VERSION 5.7 ;
BUSBITCHARS "[]" ;
DIVIDERCHAR "/" ;

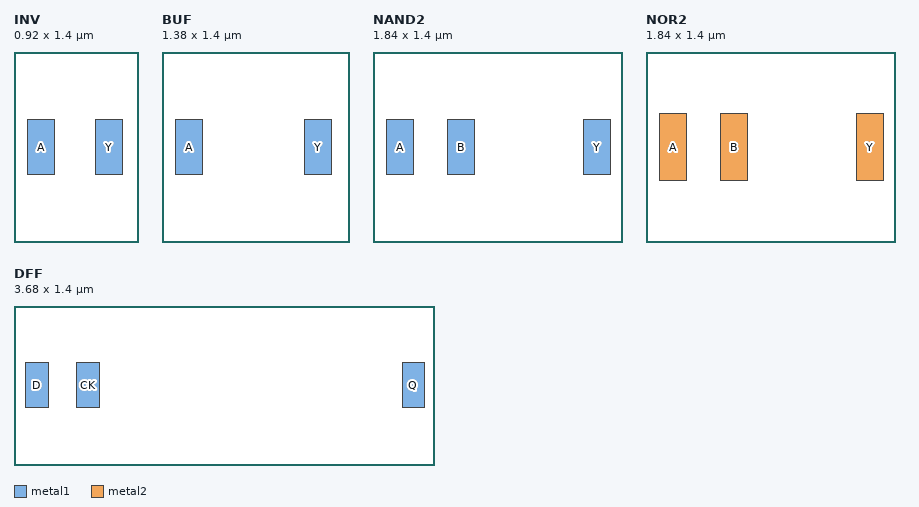
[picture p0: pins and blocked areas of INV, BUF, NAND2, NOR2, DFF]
MACRO INV
  CLASS CORE ;
  ORIGIN 0 0 ;
  SIZE 0.92 BY 1.4 ;
  SYMMETRY X Y ;
  SITE core ;
  PIN A
    DIRECTION INPUT ; USE SIGNAL ;
    PORT LAYER metal1 ; RECT 0.1 0.5 0.3 0.9 ; END
  END A
  PIN Y
    DIRECTION OUTPUT ; USE SIGNAL ;
    PORT LAYER metal1 ; RECT 0.6 0.5 0.8 0.9 ; END
  END Y
END INV

MACRO BUF
  CLASS CORE ;
  ORIGIN 0 0 ;
  SIZE 1.38 BY 1.4 ;
  SYMMETRY X Y ;
  SITE core ;
  PIN A
    DIRECTION INPUT ; USE SIGNAL ;
    PORT LAYER metal1 ; RECT 0.1 0.5 0.3 0.9 ; END
  END A
  PIN Y
    DIRECTION OUTPUT ; USE SIGNAL ;
    PORT LAYER metal1 ; RECT 1.05 0.5 1.25 0.9 ; END
  END Y
END BUF

MACRO NAND2
  CLASS CORE ;
  ORIGIN 0 0 ;
  SIZE 1.84 BY 1.4 ;
  SYMMETRY X Y ;
  SITE core ;
  PIN A
    DIRECTION INPUT ; USE SIGNAL ;
    PORT LAYER metal1 ; RECT 0.1 0.5 0.3 0.9 ; END
  END A
  PIN B
    DIRECTION INPUT ; USE SIGNAL ;
    PORT LAYER metal1 ; RECT 0.55 0.5 0.75 0.9 ; END
  END B
  PIN Y
    DIRECTION OUTPUT ; USE SIGNAL ;
    PORT LAYER metal1 ; RECT 1.55 0.5 1.75 0.9 ; END
  END Y
END NAND2

MACRO NOR2
  CLASS CORE ;
  ORIGIN 0 0 ;
  SIZE 1.84 BY 1.4 ;
  SYMMETRY X Y ;
  SITE core ;
  PIN A
    DIRECTION INPUT ; USE SIGNAL ;
    PORT LAYER metal2 ; RECT 0.1 0.45 0.3 0.95 ; END
  END A
  PIN B
    DIRECTION INPUT ; USE SIGNAL ;
    PORT LAYER metal2 ; RECT 0.55 0.45 0.75 0.95 ; END
  END B
  PIN Y
    DIRECTION OUTPUT ; USE SIGNAL ;
    PORT LAYER metal2 ; RECT 1.55 0.45 1.75 0.95 ; END
  END Y
END NOR2

MACRO DFF
  CLASS CORE ;
  ORIGIN 0 0 ;
  SIZE 3.68 BY 1.4 ;
  SYMMETRY X Y ;
  SITE core ;
  PIN D
    DIRECTION INPUT ; USE SIGNAL ;
    PORT LAYER metal1 ; RECT 0.1 0.5 0.3 0.9 ; END
  END D
  PIN CK
    DIRECTION INPUT ; USE CLOCK ;
    PORT LAYER metal1 ; RECT 0.55 0.5 0.75 0.9 ; END
  END CK
  PIN Q
    DIRECTION OUTPUT ; USE SIGNAL ;
    PORT LAYER metal1 ; RECT 3.4 0.5 3.6 0.9 ; END
  END Q
END DFF

END LIBRARY
